VERSION 5.7 ;
  NOWIREEXTENSIONATPIN ON ;
  DIVIDERCHAR "/" ;
  BUSBITCHARS "[]" ;
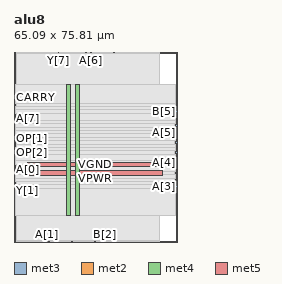
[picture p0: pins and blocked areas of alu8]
MACRO alu8
  CLASS BLOCK ;
  FOREIGN alu8 ;
  ORIGIN 0.000 0.000 ;
  SIZE 65.090 BY 75.810 ;
  PIN A[0]
    DIRECTION INPUT ;
    USE SIGNAL ;
    ANTENNAGATEAREA 0.213000 ;
    PORT
      LAYER met3 ;
        RECT 0.000 28.600 0.600 29.200 ;
    END
  END A[0]
  PIN A[1]
    DIRECTION INPUT ;
    USE SIGNAL ;
    ANTENNAGATEAREA 0.213000 ;
    PORT
      LAYER met2 ;
        RECT 12.970 0.000 13.250 0.280 ;
    END
  END A[1]
  PIN A[2]
    DIRECTION INPUT ;
    USE SIGNAL ;
    ANTENNAGATEAREA 0.213000 ;
    PORT
      LAYER met2 ;
        RECT 23.090 0.000 23.370 0.280 ;
    END
  END A[2]
  PIN A[3]
    DIRECTION INPUT ;
    USE SIGNAL ;
    ANTENNAGATEAREA 0.213000 ;
    PORT
      LAYER met3 ;
        RECT 64.490 21.800 65.090 22.400 ;
    END
  END A[3]
  PIN A[4]
    DIRECTION INPUT ;
    USE SIGNAL ;
    ANTENNAGATEAREA 0.213000 ;
    PORT
      LAYER met3 ;
        RECT 64.490 31.320 65.090 31.920 ;
    END
  END A[4]
  PIN A[5]
    DIRECTION INPUT ;
    USE SIGNAL ;
    ANTENNAGATEAREA 0.213000 ;
    PORT
      LAYER met3 ;
        RECT 64.490 43.560 65.090 44.160 ;
    END
  END A[5]
  PIN A[6]
    DIRECTION INPUT ;
    USE SIGNAL ;
    ANTENNAGATEAREA 0.213000 ;
    PORT
      LAYER met2 ;
        RECT 30.450 75.530 30.730 75.810 ;
    END
  END A[6]
  PIN A[7]
    DIRECTION INPUT ;
    USE SIGNAL ;
    ANTENNAGATEAREA 0.213000 ;
    PORT
      LAYER met3 ;
        RECT 0.000 49.000 0.600 49.600 ;
    END
  END A[7]
  PIN B[0]
    DIRECTION INPUT ;
    USE SIGNAL ;
    ANTENNAGATEAREA 0.213000 ;
    PORT
      LAYER met3 ;
        RECT 0.000 27.240 0.600 27.840 ;
    END
  END B[0]
  PIN B[1]
    DIRECTION INPUT ;
    USE SIGNAL ;
    ANTENNAGATEAREA 0.213000 ;
    PORT
      LAYER met2 ;
        RECT 13.890 0.000 14.170 0.280 ;
    END
  END B[1]
  PIN B[2]
    DIRECTION INPUT ;
    USE SIGNAL ;
    ANTENNAGATEAREA 0.213000 ;
    PORT
      LAYER met2 ;
        RECT 35.970 0.000 36.250 0.280 ;
    END
  END B[2]
  PIN B[3]
    DIRECTION INPUT ;
    USE SIGNAL ;
    ANTENNAGATEAREA 0.213000 ;
    PORT
      LAYER met3 ;
        RECT 64.490 27.240 65.090 27.840 ;
    END
  END B[3]
  PIN B[4]
    DIRECTION INPUT ;
    USE SIGNAL ;
    ANTENNAGATEAREA 0.213000 ;
    PORT
      LAYER met3 ;
        RECT 64.490 39.480 65.090 40.080 ;
    END
  END B[4]
  PIN B[5]
    DIRECTION INPUT ;
    USE SIGNAL ;
    ANTENNAGATEAREA 0.213000 ;
    PORT
      LAYER met3 ;
        RECT 64.490 51.720 65.090 52.320 ;
    END
  END B[5]
  PIN B[6]
    DIRECTION INPUT ;
    USE SIGNAL ;
    ANTENNAGATEAREA 0.213000 ;
    PORT
      LAYER met2 ;
        RECT 28.610 75.530 28.890 75.810 ;
    END
  END B[6]
  PIN B[7]
    DIRECTION INPUT ;
    USE SIGNAL ;
    ANTENNAGATEAREA 0.213000 ;
    PORT
      LAYER met3 ;
        RECT 0.000 50.360 0.600 50.960 ;
    END
  END B[7]
  PIN CARRY
    DIRECTION OUTPUT ;
    USE SIGNAL ;
    ANTENNAGATEAREA 0.126000 ;
    ANTENNADIFFAREA 0.429000 ;
    PORT
      LAYER met3 ;
        RECT 0.000 54.440 0.600 55.040 ;
    END
  END CARRY
  PIN OP[0]
    DIRECTION INPUT ;
    USE SIGNAL ;
    ANTENNAGATEAREA 0.213000 ;
    PORT
      LAYER met3 ;
        RECT 0.000 39.480 0.600 40.080 ;
    END
  END OP[0]
  PIN OP[1]
    DIRECTION INPUT ;
    USE SIGNAL ;
    ANTENNAGATEAREA 0.213000 ;
    PORT
      LAYER met3 ;
        RECT 0.000 40.840 0.600 41.440 ;
    END
  END OP[1]
  PIN OP[2]
    DIRECTION INPUT ;
    USE SIGNAL ;
    ANTENNAGATEAREA 0.213000 ;
    PORT
      LAYER met3 ;
        RECT 0.000 38.120 0.600 38.720 ;
    END
  END OP[2]
  PIN VGND
    DIRECTION INOUT ;
    USE GROUND ;
    PORT
      LAYER met4 ;
        RECT 24.340 10.640 25.940 62.800 ;
    END
    PORT
      LAYER met5 ;
        RECT 5.520 30.030 59.340 31.630 ;
    END
  END VGND
  PIN VPWR
    DIRECTION INOUT ;
    USE POWER ;
    PORT
      LAYER met4 ;
        RECT 21.040 10.640 22.640 62.800 ;
    END
    PORT
      LAYER met5 ;
        RECT 5.520 26.730 59.340 28.330 ;
    END
  END VPWR
  PIN Y[0]
    DIRECTION OUTPUT ;
    USE SIGNAL ;
    ANTENNADIFFAREA 0.702900 ;
    PORT
      LAYER met3 ;
        RECT 0.000 29.960 0.600 30.560 ;
    END
  END Y[0]
  PIN Y[1]
    DIRECTION OUTPUT ;
    USE SIGNAL ;
    ANTENNADIFFAREA 0.702900 ;
    PORT
      LAYER met3 ;
        RECT 0.000 23.160 0.600 23.760 ;
    END
  END Y[1]
  PIN Y[2]
    DIRECTION OUTPUT ;
    USE SIGNAL ;
    ANTENNADIFFAREA 0.702900 ;
    PORT
      LAYER met2 ;
        RECT 32.290 0.000 32.570 0.280 ;
    END
  END Y[2]
  PIN Y[3]
    DIRECTION OUTPUT ;
    USE SIGNAL ;
    ANTENNADIFFAREA 0.702900 ;
    PORT
      LAYER met3 ;
        RECT 64.490 24.520 65.090 25.120 ;
    END
  END Y[3]
  PIN Y[4]
    DIRECTION OUTPUT ;
    USE SIGNAL ;
    ANTENNADIFFAREA 0.702900 ;
    PORT
      LAYER met3 ;
        RECT 64.490 35.400 65.090 36.000 ;
    END
  END Y[4]
  PIN Y[5]
    DIRECTION OUTPUT ;
    USE SIGNAL ;
    ANTENNADIFFAREA 0.702900 ;
    PORT
      LAYER met3 ;
        RECT 64.490 46.280 65.090 46.880 ;
    END
  END Y[5]
  PIN Y[6]
    DIRECTION OUTPUT ;
    USE SIGNAL ;
    ANTENNADIFFAREA 0.702900 ;
    PORT
      LAYER met2 ;
        RECT 39.650 75.530 39.930 75.810 ;
    END
  END Y[6]
  PIN Y[7]
    DIRECTION OUTPUT ;
    USE SIGNAL ;
    ANTENNADIFFAREA 0.383400 ;
    PORT
      LAYER met2 ;
        RECT 17.570 75.530 17.850 75.810 ;
    END
  END Y[7]
  OBS
      LAYER nwell ;
        RECT 5.330 10.795 59.530 62.750 ;
      LAYER li1 ;
        RECT 5.520 10.795 59.340 62.645 ;
      LAYER met1 ;
        RECT 0.990 10.640 59.340 62.800 ;
      LAYER met2 ;
        RECT 1.010 75.250 17.290 75.530 ;
        RECT 18.130 75.250 28.330 75.530 ;
        RECT 29.170 75.250 30.170 75.530 ;
        RECT 31.010 75.250 39.370 75.530 ;
        RECT 40.210 75.250 57.870 75.530 ;
        RECT 1.010 0.560 57.870 75.250 ;
        RECT 1.010 0.280 12.690 0.560 ;
        RECT 13.530 0.280 13.610 0.560 ;
        RECT 14.450 0.280 22.810 0.560 ;
        RECT 23.650 0.280 32.010 0.560 ;
        RECT 32.850 0.280 35.690 0.560 ;
        RECT 36.530 0.280 57.870 0.560 ;
      LAYER met3 ;
        RECT 0.600 55.440 64.490 62.725 ;
        RECT 1.000 54.040 64.490 55.440 ;
        RECT 0.600 52.720 64.490 54.040 ;
        RECT 0.600 51.360 64.090 52.720 ;
        RECT 1.000 51.320 64.090 51.360 ;
        RECT 1.000 48.600 64.490 51.320 ;
        RECT 0.600 47.280 64.490 48.600 ;
        RECT 0.600 45.880 64.090 47.280 ;
        RECT 0.600 44.560 64.490 45.880 ;
        RECT 0.600 43.160 64.090 44.560 ;
        RECT 0.600 41.840 64.490 43.160 ;
        RECT 1.000 40.480 64.490 41.840 ;
        RECT 1.000 39.080 64.090 40.480 ;
        RECT 1.000 37.720 64.490 39.080 ;
        RECT 0.600 36.400 64.490 37.720 ;
        RECT 0.600 35.000 64.090 36.400 ;
        RECT 0.600 32.320 64.490 35.000 ;
        RECT 0.600 30.960 64.090 32.320 ;
        RECT 1.000 30.920 64.090 30.960 ;
        RECT 1.000 28.240 64.490 30.920 ;
        RECT 1.000 26.840 64.090 28.240 ;
        RECT 0.600 25.520 64.490 26.840 ;
        RECT 0.600 24.160 64.090 25.520 ;
        RECT 1.000 24.120 64.090 24.160 ;
        RECT 1.000 22.800 64.490 24.120 ;
        RECT 1.000 22.760 64.090 22.800 ;
        RECT 0.600 21.400 64.090 22.760 ;
        RECT 0.600 10.715 64.490 21.400 ;
  END
END alu8
END LIBRARY

